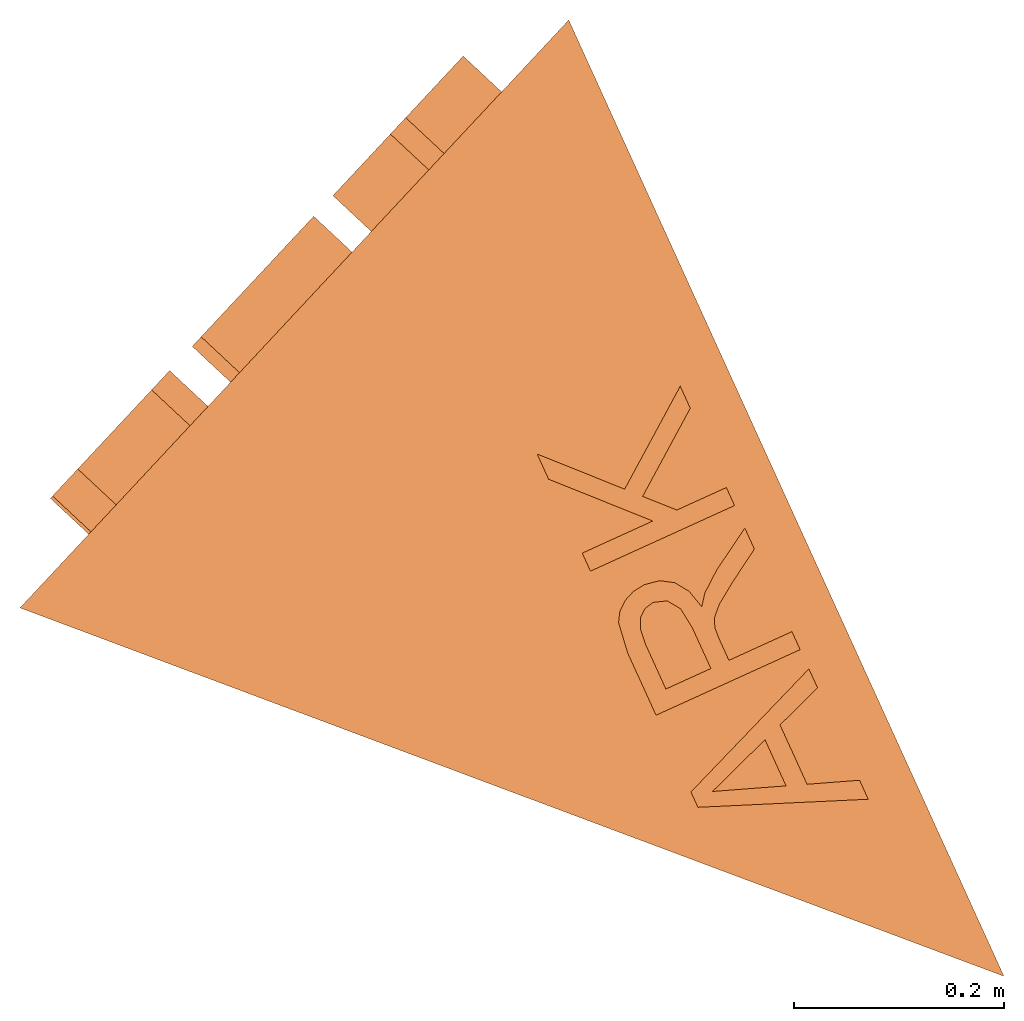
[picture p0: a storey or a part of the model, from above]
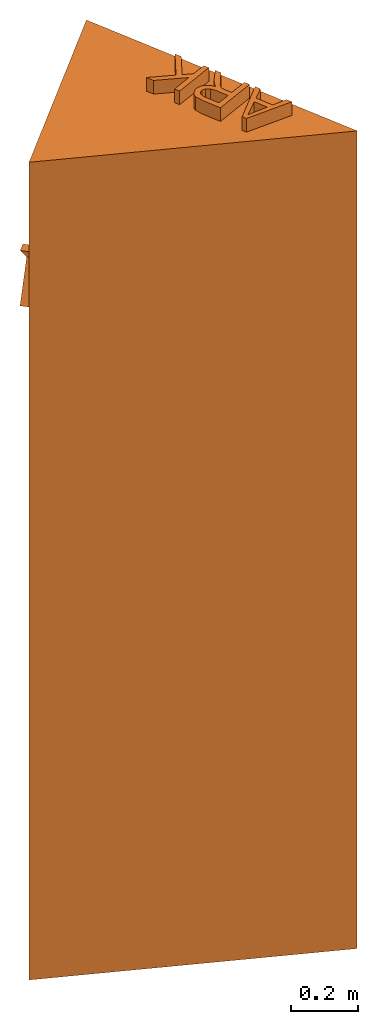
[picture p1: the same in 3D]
Properties of the parts of a building model (IFC4)

# File
Description: ViewDefinition [ReferenceView_V1.2], RevitIdentifiers [ContentGUID: 9cd8e079-0436-4ea4-8650-3dddd296d1fd, VersionGUID: 580e8274-afbe-421e-a8b7-224c4fa81504, NumberOfSaves: 417], CoordinateReference [CoordinateBase: Shared Coordinates, ProjectSite: Internal]
File name: A_52508566_Brannstasjon Drevsjø2.ifc
Time: 2026-09-22T08:41:08+01:00
Written by: ODA SDAI 25.12
Made in: Autodesk - Revit 26.4.0.32 (ENU) - 26.4.10.8

# IfcProject, 52508566
LongName: Brannstasjon Drevsjø; Phase: -

# IfcSite, Tomtens navn
RefLatitude: 59, 54, 57, 601318; RefLongitude: 10, 44, 59, 999999; RefElevation: 0 mm

# IfcBuilding, Byggets navn
LongName: Byggets navn

# IfcBuildingStorey (5)
In: Byggets navn
Name | LongName | Elevation (mm)
Level U1 | Level U1 | -3000
0-Sea Level | 0-Sea Level | 0
Level 01 | Level 01 | 2.19937e-25
Level 02 | Level 02 | 3500
Level 3 | Level 3 | 7000

# IfcSpace: BK 121:2084863, 121
In: Level 01
LongName: BK

# IfcSpace: Data 203:1993968, 203
In: Level 02
LongName: Data

# IfcSpace: Dusj D 109:1964507, 109
In: Level 01
LongName: Dusj D

# IfcSpace: Dusj H 107:1964497, 107
In: Level 01
LongName: Dusj H

# IfcSpace: EL. 122:2086236, 122
In: Level 01
LongName: EL.

# IfcSpace: Fingard. damer 104:1964506, 104
In: Level 01
LongName: Fingard. damer

# IfcSpace: Fingard. herrer 103:1964496, 103
In: Level 01
LongName: Fingard. herrer

# IfcSpace: Garasje skogbrannberedskap 118:1971460, 118
In: Level 01
LongName: Garasje skogbrannberedskap

# IfcSpace: Grovgard. d 110:1964504, 110
In: Level 01
LongName: Grovgard. d

# IfcSpace: Grovgard. h 108:1964503, 108
In: Level 01
LongName: Grovgard. h

# IfcSpace: Grovvask/lomp 111:1964502, 111
In: Level 01
LongName: Grovvask/lomp

# IfcSpace: Korridor 101:1964493, 101
In: Level 01
LongName: Korridor

# IfcSpace: Mesanin 204:1981262, 204
In: Level 02
LongName: Mesanin

# IfcSpace: Platting 206:2002072, 206
In: Level 02
LongName: Platting

# IfcSpace: Rapport 205:2087642, 205
In: Level 02
LongName: Rapport

# IfcSpace: Sivilforsvaret 131:2087587, 131
In: Level 01
LongName: Sivilforsvaret

# IfcSpace: Teknisk 120:2077556, 120
In: Level 01
LongName: Teknisk

# IfcSpace: Teknisk 202:1964515, 202
In: Level 02
LongName: Teknisk

# IfcSpace: Ubrukt areal 201:2080696, 201
In: Level 02
LongName: Ubrukt areal

# IfcSpace: Utrykningsgarderobe 102:1964509, 102
In: Level 01
LongName: Utrykningsgarderobe

# IfcSpace: Utstyrsrom/lager 115:1964525, 115
In: Level 01
LongName: Utstyrsrom/lager

# IfcSpace: VF 124:2093019, 124
In: Level 01
LongName: VF

# IfcSpace: Vask-tørk 113:1964501, 113
In: Level 01
LongName: Vask-tørk

# IfcSpace: Vaskehall 119:2018025, 119
In: Level 01
LongName: Vaskehall

# IfcSpace: Vognhall spor 1 117:1964524, 117
In: Level 01
LongName: Vognhall spor 1

# IfcSpace: Vognhall spor 2 116:1964523, 116
In: Level 01
LongName: Vognhall spor 2

# IfcSpace: WC 105:1964498, 105
In: Level 01
LongName: WC

# IfcSpace: WC 106:1964508, 106
In: Level 01
LongName: WC

# IfcSpace: WC 112:1964505, 112
In: Level 01
LongName: WC

# IfcSpace: WC 123:2093000, 123
In: Level 01
LongName: WC

# IfcBuildingElementPart (363)
Name | In | Material
12 x Metall - Malt overflate - Mørk Grå, Matt | Level 01 | Metall - Malt overflate - Mørk Grå, Matt
16 x Rustfritt Stål | Level 01 | Rustfritt Stål
19 x NO_Isolasjon - Fast | Level 01 | NO_Isolasjon - Fast
53 x Gipsplater | Level 01 | Gipsplater
41 x Stender | Level 01 | Stender
Floor:Gulv på grunn 120mm:1964344 | Level 01
4 x NO_Betong - Plasstøpt | Level 01 | NO_Betong - Plasstøpt
20 x NO_platekledning forestia | Level 01 | NO_platekledning forestia
24 x NO_Kryssfiner | Level 01 | NO_Kryssfiner
18 x NO_Baderomsplater | Level 01 | NO_Baderomsplater
2 x NO_Maling - rød | Level 02 | NO_Maling - rød
12 x Rustfritt Stål | Level 02 | Rustfritt Stål
10 x NO_Isolasjon - Fast | Level 02 | NO_Isolasjon - Fast
6 x Metall - Malt overflate - Mørk Grå, Matt | Level 02 | Metall - Malt overflate - Mørk Grå, Matt
5 x NO_Betong - Plasstøpt | Level 02 | NO_Betong - Plasstøpt
2 x NO_Vinyl | Level 02 | NO_Vinyl
2 x Floor:HD-320+ isolasjon og avretting:1964411 | Level 02
5 x Metall - Malt overflate - Mørk Grå, Matt | Level 3 | Metall - Malt overflate - Mørk Grå, Matt
6 x Rustfritt Stål | Level 3 | Rustfritt Stål
6 x NO_Isolasjon - Fast | Level 3 | NO_Isolasjon - Fast
NO_Himling (type ikke bestemt) | 104 | NO_Himling (type ikke bestemt)
NO_Himling 600x600 | 104 | NO_Himling 600x600
NO_Himling (type ikke bestemt) | 110 | NO_Himling (type ikke bestemt)
NO_Himling 600x600 | 110 | NO_Himling 600x600
NO_Himling (type ikke bestemt) | 109 | NO_Himling (type ikke bestemt)
NO_Himling 600x600 hygiene | 109 | NO_Himling 600x600 hygiene
NO_Himling (type ikke bestemt) | 103 | NO_Himling (type ikke bestemt)
NO_Himling 600x600 | 103 | NO_Himling 600x600
NO_Himling (type ikke bestemt) | 107 | NO_Himling (type ikke bestemt)
NO_Himling 600x600 hygiene | 107 | NO_Himling 600x600 hygiene
NO_Himling (type ikke bestemt) | 108 | NO_Himling (type ikke bestemt)
NO_Himling 600x600 | 108 | NO_Himling 600x600
NO_Himling (type ikke bestemt) | Level 01 | NO_Himling (type ikke bestemt)
NO_Himling 600x600 | Level 01 | NO_Himling 600x600
NO_Himling (type ikke bestemt) | 111 | NO_Himling (type ikke bestemt)
NO_Himling 600x600 | 111 | NO_Himling 600x600
4 x NO_platekledning | Level 01 | NO_platekledning
NO_Gips | Level 02 | NO_Gips
NO_Konstruksjon - Isolert | Level 02 | NO_Konstruksjon - Isolert
3 x NO_Konstruksjon - Isolert | Level 01 | NO_Konstruksjon - Isolert
NO_Himling (type ikke bestemt) | 101 | NO_Himling (type ikke bestemt)
NO_Himling 600x600 | 101 | NO_Himling 600x600
6 x NO_Maling - mørk grå | Level 01 | NO_Maling - mørk grå
6 x 231_Vegg 250mm_Betong | Level 01 | 231_Vegg 250mm_Betong
19 x Gipsplater | Level 02 | Gipsplater
2 x NO_platekledning forestia | Level 02 | NO_platekledning forestia
9 x Stender | Level 02 | Stender
NO_Metall - Rustfritt Stål-rist | Level 01 | NO_Metall - Rustfritt Stål-rist
NO_Himling (type ikke bestemt) | 106 | NO_Himling (type ikke bestemt)
NO_Himling 600x600 | 106 | NO_Himling 600x600
3 x NO_platekledning | Level 02 | NO_platekledning
NO_Himling (type ikke bestemt) | 112 | NO_Himling (type ikke bestemt)
NO_Himling 600x600 | 112 | NO_Himling 600x600
NO_Himling (type ikke bestemt) | 105 | NO_Himling (type ikke bestemt)
NO_Himling 600x600 | 105 | NO_Himling 600x600
NO_Himling (type ikke bestemt) | 113 | NO_Himling (type ikke bestemt)
NO_Himling 600x600 | 113 | NO_Himling 600x600
Floor:HD-320 mesanin +30mm:1981251 | Level 02
5 x NO_Kryssfiner | Level 02 | NO_Kryssfiner
NO_Himling (type ikke bestemt) | 120 | NO_Himling (type ikke bestemt)
NO_Himling 600x600 | 120 | NO_Himling 600x600
NO_Maling - rød | Level 01 | NO_Maling - rød
NO_Maling - rød | Level 3 | NO_Maling - rød
NO_Himling (type ikke bestemt) | 205 | NO_Himling (type ikke bestemt)
NO_Himling 600x600 | 205 | NO_Himling 600x600
NO_Himling (type ikke bestemt) | 121 | NO_Himling (type ikke bestemt)
NO_Himling 600x600 | 121 | NO_Himling 600x600
NO_Himling (type ikke bestemt) | 123 | NO_Himling (type ikke bestemt)
NO_Himling 600x600 | 123 | NO_Himling 600x600
NO_Himling (type ikke bestemt) | 124 | NO_Himling (type ikke bestemt)
NO_Himling 600x600 | 124 | NO_Himling 600x600

# IfcBuildingElementProxy: Computer_Desktop_X-ray_PACs_screens_and_keyboard_13483:Computer_Desktop_X-ray_PACs_screens_and_keyboard_13483 (2)
In: 205
Type - Material: -Computer Monitor PACs Decal, -Computer Monitor Plastic Black, <Unnamed>, - Computer Plastic Black, -Computer Keyboard Decal, Alumium, Plastic White
Name (Computer_Desktop_X-ray_PACs_screens_and_keyboard_13483:Computer_Desktop_X-ray_PACs_screens_and_keyboard_13483:...)
2106597
2106598

# IfcBuildingElementProxy: Dishwasher:Dishwasher, Dishwasher:Dishwasher:2097757
In: 205
Type - Material: <Unnamed>

# IfcBuildingElementProxy: Dryer:750x1200x1850 mm, Dryer:750x1200x1850 mm:1964970
In: 113
Type - Material: <Unnamed>, Black

# IfcBuildingElementProxy: Dryer:Tørkeskap 600x6000x1850 mm (2)
In: 113
Type - Material: <Unnamed>, Black
Name (Dryer:Tørkeskap 600x6000x1850 mm:...)
1965009
1965107

# IfcBuildingElementProxy: Handtag skåp1:Handtag skåp (34)
Type - Material: Handtag, vitt
Name (Handtag skåp1:Handtag skåp:...) | In
1965055 | 102
1965056 | 102
1965058 | 102
1965059 | 102
1965061 | 102
1965062 | 102
1965064 | 102
1965065 | 102
1965067 | 102
1965068 | 102
1965070 | 102
1965071 | 102
1965073 | 102
1965074 | 102
1965076 | 102
1965077 | 102
1965079 | 102
1965080 | 102
1965082 | 102
1965083 | 102
1965085 | 102
1965086 | 102
1965088 | 102
1965089 | 102
1965091 | 102
1965092 | 102
1965094 | 102
1965095 | 102
1965097 | 102
1965098 | 102
1965100 | 102
1965101 | 102
2084983 | 121
2084984 | 121

# IfcBuildingElementProxy: Microwave:600 x 400 x 400mm, Microwave:600 x 400 x 400mm:2098127
In: 205
Type - Material: <Unnamed>

# IfcBuildingElementProxy: NO_Origo:ARK, NO_Origo:ARK:921652
In: Level U1
Type - Material: ARK, <Unnamed>

# IfcBuildingElementProxy: Pantry_Shelving:W900 D545 (2)
In: 119
Type - Material: <Unnamed>, Shelf Top
Name (Pantry_Shelving:W900 D545:...)
2105331
2105332

# IfcBuildingElementProxy: Printer-Copier:Printer, Printer-Copier:Printer:2106596
In: 205
Type - Material: Plastic - ABS, White, Plastic - ABS, Grey, Plastic - Polycarbonate, Black
Classification: E1010800 Office Equipment (Uniformat)

# IfcBuildingElementProxy: Refrigerator_Under Counter:600x600x860mm, Refrigerator_Under Counter:600x600x860mm:2102702
In: 205
Type - Material: <Unnamed>

# IfcBuildingElementProxy: Special Equipment_Ladder_Cage:Standard, Special Equipment_Ladder_Cage:Standard:2122300
In: Level 01
Type - Material: <Unnamed>

# IfcBuildingElementProxy: Washer:1200x900x1800 mm klær, Washer:1200x900x1800 mm klær:1964969
In: 111
Type - Material: <Unnamed>

# IfcBuildingElementProxy: Washer:1290x850x1800 mm utstyr, Washer:1290x850x1800 mm utstyr:1964957
In: 111
Type - Material: <Unnamed>

# IfcBuildingElementProxy: Washer:600x600x850 mm, Washer:600x600x850 mm:1964958
In: 113
Type - Material: <Unnamed>

# IfcCovering: Compound Ceiling:H01 257_Systemhimling 600x600, tykkelse 100 (16)
Type - PredefinedType: CEILING
Name (Compound Ceiling:H01 257_Systemhimling 600x600, tykkelse 100:...) | In
1964538 | 104
1964545 | 110
1964664 | 103
1964678 | 108
1964685 | Level 01
1964692 | 111
1964847 | 101
1965118 | 106
1965170 | 112
1965181 | 105
1965213 | 113
2031679 | 120
2099162 | 205
2117964 | 121
2118016 | 123
2118024 | 124

# IfcCovering: Compound Ceiling:H02 257_Systemhimling 600x600, hygiene (2)
Type - PredefinedType: CEILING
Name (Compound Ceiling:H02 257_Systemhimling 600x600, hygiene:...) | In
1964552 | 109
1964671 | 107

# IfcDistributionPort (10)
Description: Flow; FlowDirection: SINK; PredefinedType: PIPE
Name | SystemType
InPort_1964533_1 | DOMESTICHOTWATER
InPort_1964533_2 | DOMESTICCOLDWATER
InPort_1964971_1 | DOMESTICHOTWATER
InPort_1964971_2 | DOMESTICCOLDWATER
InPort_1992489_1 | DOMESTICHOTWATER
InPort_1992489_2 | DOMESTICCOLDWATER
InPort_2084714_1 | DOMESTICHOTWATER
InPort_2084714_2 | DOMESTICCOLDWATER
InPort_2116596_1 | DOMESTICHOTWATER
InPort_2116596_2 | DOMESTICCOLDWATER

# IfcDoor: ASSA_ABLOY_FoldingDoor_FD2350P_2+2_Manual:42x45 (2)
In: Level 01
Type - PredefinedType: DOOR; Material: <Unnamed>, Aluminum - Assa Abloy - Black, Steel - Assa Abloy - Paint Finish RAL 3002 - Red
OverallHeight: 4500 mm; OverallWidth: 4200 mm; Classification: B2030 Exterior Doors (Uniformat)
Name (ASSA_ABLOY_FoldingDoor_FD2350P_2+2_Manual:42x45:...)
1967829
1967928

# IfcDoor: Enfløyet:ID02 11x21M, Enfløyet:ID02 11x21M:1992485
In: Level 02
Type - PredefinedType: DOOR; OperationType: SINGLE_SWING_LEFT; Material: Rustfritt Stål, Hvit (2)
Type - Enfløyet:ID02 11x21M:1992485:1 - PanelOperation: SWINGING
OverallHeight: 2110 mm; OverallWidth: 1110 mm; Material: Rustfritt Stål, Hvit

# IfcDoor: Enfløyet:ID03 Tredør 11x21M - EI30 (2)
In: Level 02
Type - PredefinedType: DOOR; OperationType: SINGLE_SWING_LEFT; Material: Rustfritt Stål, Hvit (2)
Type - Enfløyet:ID03 Tredør 11x21M - EI30:1992797:1 - PanelOperation: SWINGING
OverallHeight: 2110 mm; OverallWidth: 1110 mm; Material: Rustfritt Stål, Hvit
Name (Enfløyet:ID03 Tredør 11x21M - EI30:...)
1992797
2086316

# IfcDoor: Enfløyet:ID04 Tredør 9x21M, Enfløyet:ID04 Tredør 9x21M:2092488
In: Level 01
Type - PredefinedType: DOOR; OperationType: SINGLE_SWING_LEFT; Material: Rustfritt Stål, NO_Maling - Hvit, Hvit
Type - Enfløyet:ID04 Tredør 9x21M:2092488:1 - PanelOperation: SWINGING
OverallHeight: 2110 mm; OverallWidth: 910 mm

# IfcDoor: Enfløyet:ID04 Tredør 9x21M, Enfløyet:ID04 Tredør 9x21M:1964951
In: Level 01
Type - PredefinedType: DOOR; OperationType: SINGLE_SWING_RIGHT; Material: Rustfritt Stål, NO_Maling - Hvit, Hvit
Type - Enfløyet:ID04 Tredør 9x21M:1964951:1 - PanelOperation: SWINGING
OverallHeight: 2110 mm; OverallWidth: 910 mm

# IfcDoor: Enfløyet:ID04 Tredør 9x21M (2)
In: Level 01
Type - PredefinedType: DOOR; OperationType: SINGLE_SWING_RIGHT; Material: Rustfritt Stål, NO_Maling - Hvit, Hvit
Type - Enfløyet:ID04 Tredør 9x21M:1964952:1 - PanelOperation: SWINGING
OverallHeight: 2110 mm; OverallWidth: 910 mm
Name (Enfløyet:ID04 Tredør 9x21M:...)
1964952
1964973

# IfcDoor: Enfløyet:ID05 Komposittdør 10x21M (2)
In: Level 01
Type - PredefinedType: DOOR; OperationType: SINGLE_SWING_RIGHT; Material: Rustfritt Stål, Hvit (2)
Type - Enfløyet:ID05 Komposittdør 10x21M:1964434:1 - PanelOperation: SWINGING
OverallHeight: 2110 mm; OverallWidth: 1010 mm; Material: Rustfritt Stål, Hvit
Name (Enfløyet:ID05 Komposittdør 10x21M:...)
1964434
1964435

# IfcDoor: Enfløyet:ID06 Tredør 10x21M, Enfløyet:ID06 Tredør 10x21M:1964431
In: Level 01
Type - PredefinedType: DOOR; OperationType: SINGLE_SWING_LEFT; Material: Rustfritt Stål, Hvit (2)
Type - Enfløyet:ID06 Tredør 10x21M:1964431:1 - PanelOperation: SWINGING
OverallHeight: 2110 mm; OverallWidth: 1010 mm; Material: Rustfritt Stål, Hvit

# IfcDoor: Enfløyet:ID06 Tredør 10x21M (2)
In: Level 01
Type - PredefinedType: DOOR; OperationType: SINGLE_SWING_LEFT; Material: Rustfritt Stål, Hvit (2)
Type - Enfløyet:ID06 Tredør 10x21M:1964948:1 - PanelOperation: SWINGING
OverallHeight: 2110 mm; OverallWidth: 1010 mm; Material: Rustfritt Stål, Hvit
Name (Enfløyet:ID06 Tredør 10x21M:...)
1964948
1964949

# IfcDoor: Enfløyet:ID07 Tredør 10x21M EI60, Enfløyet:ID07 Tredør 10x21M EI60:1964855
In: Level 01
Type - PredefinedType: DOOR; OperationType: SINGLE_SWING_RIGHT; Material: Rustfritt Stål, Hvit (2)
Type - Enfløyet:ID07 Tredør 10x21M EI60:1964855:1 - PanelOperation: SWINGING
OverallHeight: 2110 mm; OverallWidth: 1010 mm; Material: Rustfritt Stål, Hvit

# IfcDoor: Enfløyet:ID08 11x21M EI60CSa, Enfløyet:ID08 11x21M EI60CSa:1964432
In: Level 01
Type - PredefinedType: DOOR; OperationType: SINGLE_SWING_LEFT; Material: Rustfritt Stål, Hvit (2)
Type - Enfløyet:ID08 11x21M EI60CSa:1964432:1 - PanelOperation: SWINGING
OverallHeight: 2110 mm; OverallWidth: 1110 mm; Material: Rustfritt Stål, Hvit

# IfcDoor: Enfløyet:ID09 ståldør 13x21M EI30 2, Enfløyet:ID09 ståldør 13x21M EI30 2:1964436
In: Level 01
Type - PredefinedType: DOOR; OperationType: SINGLE_SWING_RIGHT; Material: Rustfritt Stål, Hvit (2)
Type - Enfløyet:ID09 ståldør 13x21M EI30 2:1964436:1 - PanelOperation: SWINGING
OverallHeight: 2110 mm; OverallWidth: 1310 mm; Material: Rustfritt Stål, Hvit

# IfcDoor: Enfløyet:ID1 Glassdør 11x21M 38dB, Enfløyet:ID1 Glassdør 11x21M 38dB:2087617
In: Level 02
Type - PredefinedType: DOOR; OperationType: SINGLE_SWING_LEFT; Material: Rustfritt Stål, Hvit (2), NO_Glass
Type - Enfløyet:ID1 Glassdør 11x21M 38dB:2087617:1 - PanelOperation: SWINGING
OverallHeight: 2110 mm; OverallWidth: 1110 mm; Material: Rustfritt Stål, Hvit, NO_Glass

# IfcDoor: Enfløyet:ID10 Stålsdør 10x21M, Enfløyet:ID10 Stålsdør 10x21M:2092397
In: Level 01
Type - PredefinedType: DOOR; OperationType: SINGLE_SWING_LEFT; Material: Rustfritt Stål, Hvit (2)
Type - Enfløyet:ID10 Stålsdør 10x21M:2092397:1 - PanelOperation: SWINGING
OverallHeight: 2110 mm; OverallWidth: 1010 mm; Material: Rustfritt Stål, Hvit

# IfcDoor: Enfløyet:ID11 Tredør 10x21M (2)
In: Level 01
Type - PredefinedType: DOOR; OperationType: SINGLE_SWING_LEFT; Material: Rustfritt Stål, Hvit (2)
Type - Enfløyet:ID11 Tredør 10x21M:1964950:1 - PanelOperation: SWINGING
OverallHeight: 2110 mm; OverallWidth: 1010 mm; Material: Rustfritt Stål, Hvit
Name (Enfløyet:ID11 Tredør 10x21M:...)
1964950
2085154

# IfcDoor: Enfløyet:ID11 Tredør 10x21M, Enfløyet:ID11 Tredør 10x21M:1964953
In: Level 01
Type - PredefinedType: DOOR; OperationType: SINGLE_SWING_RIGHT; Material: Rustfritt Stål, Hvit (2)
Type - Enfløyet:ID11 Tredør 10x21M:1964953:1 - PanelOperation: SWINGING
OverallHeight: 2110 mm; OverallWidth: 1010 mm; Material: Rustfritt Stål, Hvit

# IfcDoor: Enfløyet:ID13 Ståldør 10x21M EI30Sa, Enfløyet:ID13 Ståldør 10x21M EI30Sa:2077570
In: Level 01
Type - PredefinedType: DOOR; OperationType: SINGLE_SWING_LEFT; Material: Rustfritt Stål, Hvit (2)
Type - Enfløyet:ID13 Ståldør 10x21M EI30Sa:2077570:1 - PanelOperation: SWINGING
OverallHeight: 2110 mm; OverallWidth: 1010 mm; Material: Rustfritt Stål, Hvit

# IfcDoor: Enfløyet:YD01 Glassdør sprosse 11x21M, Enfløyet:YD01 Glassdør sprosse 11x21M:2075855
In: Level 01
Type - PredefinedType: DOOR; OperationType: SINGLE_SWING_LEFT; Material: Rustfritt Stål, NO_Maling - mørk grå, NO_Glass - Klart, NO_Maling - sort
Type - Enfløyet:YD01 Glassdør sprosse 11x21M:2075855:1 - PanelOperation: SWINGING
OverallHeight: 2110 mm; OverallWidth: 1110 mm

# IfcDoor: Enfløyet:YD02 Ytterdør 11x21M mørk grå, Enfløyet:YD02 Ytterdør 11x21M mørk grå:2087068
In: Level 01
Type - PredefinedType: DOOR; OperationType: SINGLE_SWING_LEFT; Material: Rustfritt Stål, NO_Maling - mørk grå, NO_Maling - sort
Type - Enfløyet:YD02 Ytterdør 11x21M mørk grå:2087068:1 - PanelOperation: SWINGING
OverallHeight: 2110 mm; OverallWidth: 1110 mm

# IfcDoor: Enfløyet:YD02 Ytterdør 11x21M mørk grå, Enfløyet:YD02 Ytterdør 11x21M mørk grå:1970705
In: Level 01
Type - PredefinedType: DOOR; OperationType: SINGLE_SWING_RIGHT; Material: Rustfritt Stål, NO_Maling - mørk grå, NO_Maling - sort
Type - Enfløyet:YD02 Ytterdør 11x21M mørk grå:1970705:1 - PanelOperation: SWINGING
OverallHeight: 2110 mm; OverallWidth: 1110 mm

# IfcDoor: Garage Door_3:P03 2500 x 2100, Garage Door_3:P03 2500 x 2100:1964530
In: Level 01
Type - PredefinedType: DOOR; Material: NO_Door - Frame Painted, Beslag, <Unnamed>, NO_Door - Panel
OverallHeight: 2100 mm; OverallWidth: 2500 mm

# IfcDoor: Garage Door_9:4200 x 4500, Garage Door_9:4200 x 4500:1965248
In: Level 01
Type - PredefinedType: DOOR; Material: Steel - Assa Abloy - Paint Finish RAL 3002 - Red (2), NO_Glass - Klart, NO_Door - Frame Painted
OverallHeight: 4500 mm; OverallWidth: 4200 mm; Material: Steel - Assa Abloy - Paint Finish RAL 3002 - Red, NO_Glass - Klart, NO_Door - Frame Painted

# IfcDoor: Garage Door_9:4200 x 4500 P02B, Garage Door_9:4200 x 4500 P02B:2087061
In: Level 01
Type - PredefinedType: DOOR; Material: Steel - Assa Abloy - Paint Finish RAL 3002 - Red (2), NO_Glass - Klart, NO_Door - Frame Painted
OverallHeight: 4500 mm; OverallWidth: 4200 mm; Material: Steel - Assa Abloy - Paint Finish RAL 3002 - Red, NO_Glass - Klart, NO_Door - Frame Painted

# IfcDoor: Garage Door_9:P04 2700 x 3000, Garage Door_9:P04 2700 x 3000:1971641
In: Level 01
Type - PredefinedType: DOOR; Material: Steel - Assa Abloy - Paint Finish RAL 3002 - Red (2), NO_Glass - Klart, NO_Door - Frame Painted
OverallHeight: 3000 mm; OverallWidth: 2700 mm; Material: Steel - Assa Abloy - Paint Finish RAL 3002 - Red, NO_Glass - Klart, NO_Door - Frame Painted

# IfcDoor: M_Door_ID_Cased-Opening:1200 x 2110mm 2, M_Door_ID_Cased-Opening:1200 x 2110mm 2:1964433
In: Level 01
Type - PredefinedType: DOOR; Material: <Unnamed>
OverallHeight: 2110 mm; OverallWidth: 1200 mm

# IfcDoor: M_Door_ID_Cased-Opening:910 x 2110mm (2)
In: Level 01
Type - PredefinedType: DOOR; Material: <Unnamed>
OverallHeight: 2110 mm; OverallWidth: 910 mm
Name (M_Door_ID_Cased-Opening:910 x 2110mm:...)
1965007
1965008

# IfcDoor: Tofløyet:ID12 Stålsdør 16x21M EI30Sa, Tofløyet:ID12 Stålsdør 16x21M EI30Sa:2076329
In: Level 01
Type - PredefinedType: DOOR; OperationType: DOUBLE_DOOR_SINGLE_SWING; Material: Hvit (2), Rustfritt Stål
Type - Tofløyet:ID12 Stålsdør 16x21M EI30Sa:2076329:1 - PanelDepth: 40 mm; PanelOperation: SWINGING; PanelWidth: 0.374214; PanelPosition: LEFT
Type - Tofløyet:ID12 Stålsdør 16x21M EI30Sa:2076329:2 - PanelDepth: 40 mm; PanelOperation: SWINGING; PanelWidth: 0.625786; PanelPosition: RIGHT
OverallHeight: 2110 mm; OverallWidth: 1610 mm; Material: Hvit, Rustfritt Stål

# IfcDoor: Tofløyet:ID14 Tredør 16x21M EI30Sa, Tofløyet:ID14 Tredør 16x21M EI30Sa:2085995
In: Level 01
Type - PredefinedType: DOOR; OperationType: DOUBLE_DOOR_SINGLE_SWING; Material: Hvit (2), Rustfritt Stål
Type - Tofløyet:ID14 Tredør 16x21M EI30Sa:2085995:1 - PanelDepth: 40 mm; PanelOperation: SWINGING; PanelWidth: 0.374214; PanelPosition: LEFT
Type - Tofløyet:ID14 Tredør 16x21M EI30Sa:2085995:2 - PanelDepth: 40 mm; PanelOperation: SWINGING; PanelWidth: 0.625786; PanelPosition: RIGHT
OverallHeight: 2110 mm; OverallWidth: 1610 mm; Material: Hvit, Rustfritt Stål

# IfcFlowTerminal: IS_Ceraflex_B5128_BIM_IT:B5128AA - CERAFLEX SNK MXR EXPSD TUB.SPT/235MM (5)
Type - Material: 2af18724_cdc2_442c_8398_5f3f990449a0
Classification: C1030200 Bath & Toilet Accessories (Uniformat)
Name (IS_Ceraflex_B5128_BIM_IT:B5128AA - CERAFLEX SNK MXR EXPSD TUB.SPT/235MM:...) | In
1964533 | 116
1964971 | 113
1992489 | 202
2084714 | 121
2116596 | 131

# IfcFlowTerminal: M_Sink Kitchen-Single:760 x 535mm, M_Sink Kitchen-Single:760 x 535mm:2098303
In: 205
Type - Material: Metal - Steel, Polished

# IfcFlowTerminal: Shower_01:Shower_01 (5)
Type - Material: <Unnamed>
Name (Shower_01:Shower_01:...) | In
1964766 | 109
1964767 | 109
1964961 | 107
1964986 | 107
1964987 | 107

# IfcFlowTerminal: Sink Vanity-Square:700 x500 x 300 (2)
In: 111
Type - Material: EU_Metal Aluminium, Polished Plain, EU_Metal Stainless Steel, Polished Plain
Name (Sink Vanity-Square:700 x500 x 300:...)
1965011
1965012

# IfcFlowTerminal: Sink Vanity-Square:900 x 700 x 500, Sink Vanity-Square:900 x 700 x 500:1965010
In: 111
Type - Material: EU_Metal Aluminium, Polished Plain, EU_Metal Stainless Steel, Polished Plain

# IfcFlowTerminal: Sink_01:500x350 (8)
Type - Material: Metal - Chrome, Porslin
Name (Sink_01:500x350:...) | In
1964946 | 108
1964947 | 110
1964963 | 105
1964964 | 104
1964967 | 112
1964968 | 103
1964984 | 106
2092192 | 123

# IfcFlowTerminal: Sink_03:Middels (5)
Type - Material: Metal - Aluminium
Name (Sink_03:Middels:...) | In
1964534 | 116
1965023 | 113
1993845 | 202
2084552 | 121
2116409 | 131

# IfcFlowTerminal: WC-Wall:Wall_Hung_WC-Valverfa_2893[1] (4)
Type - Material: Seat Finish, Pan Finish
Name (WC-Wall:Wall_Hung_WC-Valverfa_2893[1]:...) | In
1964945 | 105
1964976 | 112
1964982 | 106
2091680 | 123

# IfcFurniture: Benkeskap-3 skuff:600, Benkeskap-3 skuff:600:2098304
In: 205
Type - Material: Cabinets, <Unnamed>

# IfcFurniture: Chair Desk 2:Chair-Task Arms (2)
In: 205
Type - Material: Textile - Slate Blue, Plastic - Black
Classification: E2020200 Furniture & Accessories (Uniformat)
Name (Chair Desk 2:Chair-Task Arms:...)
2106594
2106595

# IfcFurniture: Detention_Bunk-WallMnt:Double-Bunk, Detention_Bunk-WallMnt:Double-Bunk:2106600
In: 205
Type - Material: <Unnamed>
Classification: E1020600 Detention Equipment (Uniformat)

# IfcFurniture: Overskap-Enkel dør:600 (2)
In: 205
Type - Material: Cabinets
Name (Overskap-Enkel dør:600:...)
2098632
2099032

# IfcFurniture: Overskap-Enkel dør:600 H500, Overskap-Enkel dør:600 H500:2098573
In: 205
Type - Material: Cabinets

# IfcFurniture: PLANK_BENCH_TABLE:0660-01 NATURAL (6)
In: 102
Type - Material: PLANK_WOOD_NATURAL
Name (PLANK_BENCH_TABLE:0660-01 NATURAL:...)
1965013
1965015
1965016
1965017
1965102
1965103

# IfcFurniture: PLANK_BENCH_TABLE:Benk 1200, PLANK_BENCH_TABLE:Benk 1200:1965111
In: 103
Type - Material: PLANK_WOOD_NATURAL

# IfcFurniture: Storage_Shelf_01:Oppbevaring B800xD600xH1800 2 (7)
In: 115
Type - Material: <Unnamed>
Classification: E2020200 Furniture & Accessories (Uniformat)
Name (Storage_Shelf_01:Oppbevaring B800xD600xH1800 2:...)
1965188
1965189
1965190
1965191
1965192
1965193
1965194

# IfcFurniture: Table_01:H500 D700 W1200 (2)
Type - Material: <Unnamed>
Name (Table_01:H500 D700 W1200:...) | In
1964978 | 111
1964979 | 113

# IfcFurniture: Table_Office_01:72" 1200 lang, Table_Office_01:72" 1200 lang:2106599
In: 205
Type - Material: Furniture_Watson_Seven_Leg, <Unnamed>

# IfcFurniture: Table_Office_01:72" 3100 mm lang, Table_Office_01:72" 3100 mm lang:2106593
In: 205
Type - Material: Furniture_Watson_Seven_Leg, <Unnamed>

# IfcFurniture: Wardrobe Double:700 (16)
In: 102
Type - Material: Skåpstomme, vit (2), Skåpdörr, vit
Material: Skåpstomme, vit, Skåpdörr, vit
Name (Wardrobe Double:700:...)
1965054
1965057
1965060
1965063
1965066
1965069
1965072
1965075
1965078
1965081
1965084
1965087
1965090
1965093
1965096
1965099

# IfcFurniture: Wardrobe Double:800 2, Wardrobe Double:800 2:2084982
In: 121
Type - Material: Skåpstomme, vit (2), Skåpdörr, vit
Material: Skåpstomme, vit, Skåpdörr, vit

# IfcFurniture: Worktop:600mm Depth uten vask eller utfresning, Worktop:600mm Depth uten vask eller utfresning:1970112
In: 116
Type - Material: Counter Top

# IfcFurniture: Worktop:800mm Depth uten vask, Worktop:800mm Depth uten vask:1964965
In: 111
Type - Material: Counter Top

# IfcFurniture: Worktop:with sink, Worktop:with sink:2098301
In: 205
Type - Material: Counter Top

# IfcFurniture: ^ 275_Public_Locker02 x2 w Bench:300x300+200 (10)
Type - Material: Paint - Grey, Paint - White
Name (^ 275_Public_Locker02 x2 w Bench:300x300+200:...) | In
1964750 | 104
1964751 | 104
1964752 | 104
1964753 | 104
1964755 | 103
1964756 | 103
1964757 | 103
1964758 | 103
1964759 | 103
1965112 | 103

# IfcMember: Stringer:Stringer - Metal - 45 mm Width (10)
In: Level 01
Type - PredefinedType: STRINGER
Material: Stål
Name (Assembled Stair:Stair:...)
1964990 Stringer 1
1964990 Stringer 2
2088389 Stringer 1
2088389 Stringer 2
2088389 Stringer 3
2088389 Stringer 4
2088389 Stringer 5
2088389 Stringer 6
2088389 Stringer 7
2088389 Stringer 8

# IfcOpeningElement (73)
PredefinedType: OPENING
Name | In
2 x Basic Wall:IV20 242- Utforing isolert Stender(95) gips:1964762:1 | Level 02
2 x Basic Wall:IV20 242- Utforing isolert Stender(95) gips:1964762:2 | Level 02
2 x Basic Wall:IV20 242- Utforing isolert Stender(95) gips:1964762:3 | Level 02
Basic Wall:IV15 Gips kryssfiner 95 stålstender +15mm kryssfiner+baderomsplater 2:1964960:1 | Level 01
Basic Wall:IV11 95 Utforing 15mm kryssfiner baderomsplater 2:1965105:1 | Level 01
3 x Basic Wall:YV02 Sandwichvegg 200:2095643:1 | Level 02
3 x Basic Wall:YV02 Sandwichvegg 200:2095643:2 | Level 02
3 x Basic Wall:YV02 Sandwichvegg 200:2095643:3 | Level 02
3 x Basic Wall:YV02 Sandwichvegg 200:2095643:4 | Level 02
3 x Basic Wall:YV02 Sandwichvegg 200:2095643:5 | Level 02
3 x Basic Wall:YV02 Sandwichvegg 200:2095643:6 | Level 02
Enfløyet:ID06 Tredør 10x21M:1964431:1 | Level 01
Enfløyet:ID08 11x21M EI60CSa:1964432:1 | Level 01
M_Door_ID_Cased-Opening:1200 x 2110mm 2:1964433:1 | Level 01
Enfløyet:ID05 Komposittdør 10x21M:1964434:1 | Level 01
Enfløyet:ID05 Komposittdør 10x21M:1964435:1 | Level 01
Enfløyet:ID09 ståldør 13x21M EI30 2:1964436:1 | Level 01
Åpningsvindu:V02 8x19M:1964464:1 | Level 02
Fastvindu:V01 13x19M:1964465:1 | Level 02
Fastvindu:V01 13x19M:1964466:1 | Level 02
Garage Door_3:P03 2500 x 2100:1964530:1 | Level 01
Enfløyet:ID07 Tredør 10x21M EI60:1964855:1 | Level 01
Enfløyet:ID06 Tredør 10x21M:1964948:1 | Level 01
Enfløyet:ID06 Tredør 10x21M:1964949:1 | Level 01
Enfløyet:ID11 Tredør 10x21M:1964950:1 | Level 01
Enfløyet:ID04 Tredør 9x21M:1964951:1 | Level 01
Enfløyet:ID04 Tredør 9x21M:1964952:1 | Level 01
Enfløyet:ID11 Tredør 10x21M:1964953:1 | Level 01
Enfløyet:ID04 Tredør 9x21M:1964973:1 | Level 01
M_Door_ID_Cased-Opening:910 x 2110mm:1965007:1 | Level 01
M_Door_ID_Cased-Opening:910 x 2110mm:1965008:1 | Level 01
Garage Door_9:4200 x 4500:1965248:1 | Level 01
ASSA_ABLOY_FoldingDoor_FD2350P_2+2_Manual:42x45:1967829:1 | Level 01
ASSA_ABLOY_FoldingDoor_FD2350P_2+2_Manual:42x45:1967928:1 | Level 01
Fastvindu:V03 Fastvindu 14x10M:1968759:1 | Level 02
Fastvindu:V03 Fastvindu 14x10M:1968941:1 | Level 02
Fastvindu:V03 Fastvindu 14x10M:1968995:1 | Level 02
Fastvindu:V03 Fastvindu 14x10M:1969089:1 | Level 02
Fastvindu:V03 Fastvindu 14x10M:1969251:1 | Level 02
Fastvindu:V03 Fastvindu 14x10M:1969471:1 | Level 02
Enfløyet:YD02 Ytterdør 11x21M mørk grå:1970705:1 | Level 01
Garage Door_9:P04 2700 x 3000:1971641:1 | Level 01
Enfløyet:ID02 11x21M:1992485:1 | Level 02
Enfløyet:ID03 Tredør 11x21M - EI30:1992797:1 | Level 02
Fastvindu:V01 13x19M:1994775:1 | Level 02
Fastvindu:V01 13x19M:2005449:1 | Level 02
Enfløyet:YD01 Glassdør sprosse 11x21M:2075855:1 | Level 01
Tofløyet:ID12 Stålsdør 16x21M EI30Sa:2076329:1 | Level 01
Enfløyet:ID13 Ståldør 10x21M EI30Sa:2077570:1 | Level 01
Enfløyet:ID11 Tredør 10x21M:2085154:1 | Level 01
Tofløyet:ID14 Tredør 16x21M EI30Sa:2085995:1 | Level 01
Enfløyet:ID03 Tredør 11x21M - EI30:2086316:1 | Level 02
Garage Door_9:4200 x 4500 P02B:2087061:1 | Level 01
Enfløyet:YD02 Ytterdør 11x21M mørk grå:2087068:1 | Level 01
Enfløyet:ID1 Glassdør 11x21M 38dB:2087617:1 | Level 02
Enfløyet:ID10 Stålsdør 10x21M:2092397:1 | Level 01
Enfløyet:ID04 Tredør 9x21M:2092488:1 | Level 01
Åpningsvindu:V04 8x19M:2126264:1 | Level 02

# IfcRailing: Railing:1100mm Stål Ø30 cc120 (3)
Material: <Unnamed>, Tre
Name (Railing:1100mm Stål Ø30 cc120:...) | In
1981258 | Level 02
2088689 | Level 01
2088693 | Level 01

# IfcRailing: Railing:900, Railing:900:1964999
In: Level 01
Material: <Unnamed>

# IfcRailing: Railing:900mm pipe, Railing:900mm pipe:1964995
In: Level 01
Material: <Unnamed>

# IfcRailing: Railing:Rekkverk 900mm rør - Top Rail, Railing:Rekkverk 900mm rør - Top Rail:1965037
In: Level 01
Material: <Unnamed>

# IfcRoof: Basic Roof:Warm Roof - TRP, Basic Roof:Warm Roof - TRP:1964443
In: Level 3
Material: NO_Asfaltpapp, NO_Isolasjon - Fast (2), <Unnamed>, Tak - Metall

# IfcSlab: Basic Roof:Standard 150 (2)
In: Level 02
Type - PredefinedType: ROOF
Material: Default Roof(1)
Name (Basic Roof:Standard 150:...)
2083605
2084034

# IfcSlab: Floor:Gulv på grunn 120mm, Floor:Gulv på grunn 120mm:1964344
In: Level 01
Type - PredefinedType: FLOOR

# IfcSlab: Floor:HD-320 mesanin +30mm, Floor:HD-320 mesanin +30mm:1981251
In: Level 02
Type - PredefinedType: FLOOR

# IfcSlab: Floor:HD-320+ isolasjon og avretting, Floor:HD-320+ isolasjon og avretting:1964411
In: Level 02
Type - PredefinedType: FLOOR

# IfcSlab: Floor:Rist, Floor:Rist:1965030
In: Level 01
Type - PredefinedType: FLOOR

# IfcSlab: Non-Monolithic Landing:Ikke monolittisk trappeavsats, Assembled Stair:Stair:2088389 Landing 1
In: Level 01
Type - PredefinedType: LANDING
Material: Stål

# IfcStair: Assembled Stair:Ståltrapp A, Assembled Stair:Stair:2088389
In: Level 01
Type - PredefinedType: HALF_TURN_STAIR

# IfcStair: Assembled Stair:Ståltrapp A, Assembled Stair:Stair:1964990
In: Level 01
Type - PredefinedType: STRAIGHT_RUN_STAIR

# IfcStairFlight: Non-Monolithic Run:Stål Trinn 30mm (3)
In: Level 01
Type - PredefinedType: STRAIGHT
Material: Stål
Name (Assembled Stair:Stair:...)
1964990 Run 1
2088389 Run 1
2088389 Run 2

# IfcWall: Basic Wall:IV01 - Gipsx2 Stender Gipsx2-147mm (3)
In: Level 01
Type - PredefinedType: STANDARD
Name (Basic Wall:IV01 - Gipsx2 Stender Gipsx2-147mm:...)
1964341
2084480
2085877

# IfcWall: Basic Wall:IV02 Gips Stender Gips-120mm (11)
Type - PredefinedType: STANDARD
Name (Basic Wall:IV02 Gips Stender Gips-120mm:...) | In
1964942 | Level 01
1964962 | Level 01
1964972 | Level 01
1964980 | Level 01
1964981 | Level 01
1965239 | Level 01
1993638 | Level 02
1993686 | Level 02
2091519 | Level 01
2091576 | Level 01
2091616 | Level 01

# IfcWall: Basic Wall:IV03 Gips Stender Forestia 120mm (2)
In: Level 01
Type - PredefinedType: STANDARD
Name (Basic Wall:IV03 Gips Stender Forestia 120mm:...)
1964374
1964375

# IfcWall: Basic Wall:IV04 - Gipsx2 Stender-kryssfiner- Gips-147mm, Basic Wall:IV04 - Gipsx2 Stender-kryssfiner- Gips-147mm:1992476
In: Level 02
Type - PredefinedType: STANDARD

# IfcWall: Basic Wall:IV05 - Forestia+Gips- Stender-kryssfiner- Gips (4)
Type - PredefinedType: STANDARD
Name (Basic Wall:IV05 - Forestia+Gips- Stender-kryssfiner- Gips:...) | In
1965022 | Level 01
1965108 | Level 01
1965109 | Level 01
1992478 | Level 02

# IfcWall: Basic Wall:IV07 Gips 95 stålstender +15mm kryssfiner+baderomsplater (2)
In: Level 01
Type - PredefinedType: STANDARD
Name (Basic Wall:IV07 Gips 95 stålstender +15mm kryssfiner+baderomsplater:...)
1964376
1964761

# IfcWall: Basic Wall:IV08 Forestia 95 stålstender +15mm kryssfiner+baderomsplater 2 (4)
In: Level 01
Type - PredefinedType: STANDARD
Name (Basic Wall:IV08 Forestia 95 stålstender +15mm kryssfiner+baderomsplater 2:...)
1964943
1964966
1965195
1965196

# IfcWall: Basic Wall:IV09 Badromsplate+15mm kryssf+ 95 stålstender +15mm kryssfiner+baderomsplater 2 (2)
In: Level 01
Type - PredefinedType: STANDARD
Name (Basic Wall:IV09 Badromsplate+15mm kryssf+ 95 stålstender +15mm kryssfiner+baderomsplater 2:...)
1964959
1964988

# IfcWall: Basic Wall:IV10 Forestia 95 Stender Forestia (3)
In: Level 01
Type - PredefinedType: STANDARD
Name (Basic Wall:IV10 Forestia 95 Stender Forestia:...)
1964974
1964975
1964989

# IfcWall: Basic Wall:IV11 95 Utforing 15mm kryssfiner baderomsplater 2 (2)
In: Level 01
Type - PredefinedType: STANDARD
Name (Basic Wall:IV11 95 Utforing 15mm kryssfiner baderomsplater 2:...)
1964985
1965105

# IfcWall: Basic Wall:IV12 Utforing Stender(48)-Forestia (3)
In: Level 01
Type - PredefinedType: STANDARD
Name (Basic Wall:IV12 Utforing Stender(48)-Forestia:...)
1964856
1965210
1970236

# IfcWall: Basic Wall:IV13 Utforing 198 stender+Forestia, Basic Wall:IV13 Utforing 198 stender+Forestia:1964977
In: Level 01
Type - PredefinedType: STANDARD

# IfcWall: Basic Wall:IV14 Gips 95 Stender kryssfiner Gips, Basic Wall:IV14 Gips 95 Stender kryssfiner Gips:1964760
In: Level 01
Type - PredefinedType: STANDARD

# IfcWall: Basic Wall:IV15 Gips kryssfiner 95 stålstender +15mm kryssfiner+baderomsplater 2 (3)
In: Level 01
Type - PredefinedType: STANDARD
Name (Basic Wall:IV15 Gips kryssfiner 95 stålstender +15mm kryssfiner+baderomsplater 2:...)
1964944
1964960
1965197

# IfcWall: Basic Wall:IV16 -Utforing Gips 198Stender 13+198, Basic Wall:IV16 -Utforing Gips 198Stender 13+198:1964983
In: Level 01
Type - PredefinedType: STANDARD

# IfcWall: Basic Wall:IV17 - Utforing lekt+fasadeplater (6)
Type - PredefinedType: STANDARD
Name (Basic Wall:IV17 - Utforing lekt+fasadeplater:...) | In
1964746 | Level 01
1964747 | Level 01
1964748 | Level 01
1965144 | Level 02
1965145 | Level 02
1965146 | Level 02

# IfcWall: Basic Wall:IV18 -Gips kryssfiner Stender kryssfiner-baderomsplater-13+15+200+15+11, Basic Wall:IV18 -Gips kryssfiner Stender kryssfiner-baderomsplater-13+15+200+15+11:1964765
In: Level 01
Type - PredefinedType: STANDARD

# IfcWall: Basic Wall:IV20 242- Utforing isolert Stender(95) gips, Basic Wall:IV20 242- Utforing isolert Stender(95) gips:1964762
In: Level 02
Type - PredefinedType: STANDARD

# IfcWall: Basic Wall:IV21 Betong 200 (6)
Type - PredefinedType: STANDARD
Name (Basic Wall:IV21 Betong 200:...) | In
1964372 | Level 01
1964373 | Level 01
1964384 | Level 02
1964717 | Level 01
1964956 | Level 01
1992466 | Level 02

# IfcWall: Basic Wall:IV23 Dusjvegg (3)
In: Level 01
Type - PredefinedType: STANDARD
Name (Basic Wall:IV23 Dusjvegg:...)
1965005
1965006
1965024

# IfcWall: Basic Wall:IV24 - Forestia+Gips- Stende4+2xgips, Basic Wall:IV24 - Forestia+Gips- Stende4+2xgips:1964921
In: Level 02
Type - PredefinedType: STANDARD

# IfcWall: Basic Wall:IV25 - 2xGips- Stende4+2xgips 2, Basic Wall:IV25 - 2xGips- Stende4+2xgips 2:1964922
In: Level 02
Type - PredefinedType: STANDARD

# IfcWall: Basic Wall:RIB YV-Betong_250mm+100iso (6)
In: Level 01
Type - PredefinedType: STANDARD
Name (Basic Wall:RIB YV-Betong_250mm+100iso:...)
1964885
1964887
1971344
2087058
2087059
2087067

# IfcWall: Basic Wall:YV02 Sandwichvegg 200 (19)
Type - PredefinedType: STANDARD
Name (Basic Wall:YV02 Sandwichvegg 200:...) | In
1964336 | Level 01
1964338 | Level 01
1964339 | Level 01
1964380 | Level 02
1964381 | Level 02
1964448 | Level 3
1964449 | Level 3
1964450 | Level 3
1964451 | Level 3
1971143 | Level 01
1986782 | Level 02
2080388 | Level 02
2087047 | Level 01
2087048 | Level 01
2087049 | Level 01
2087415 | Level 02
2094941 | Level 01
2095643 | Level 02
2095968 | Level 3

# IfcWall: Basic Wall:YV02 Sandwichvegg 200 rød (4)
Type - PredefinedType: STANDARD
Name (Basic Wall:YV02 Sandwichvegg 200 rød:...) | In
1964378 | Level 02
2094861 | Level 01
2095347 | Level 02
2096150 | Level 3

# IfcWindow: Fastvindu:V01 13x19M (4)
In: Level 02
Type - PredefinedType: WINDOW; Material: NO_Maling - mørk grå, NO_Glass - Klart, Hvit
OverallHeight: 1910 mm; OverallWidth: 1310 mm
Name (Fastvindu:V01 13x19M:...)
1964465
1964466
1994775
2005449

# IfcWindow: Fastvindu:V03 Fastvindu 14x10M (6)
In: Level 02
Type - PredefinedType: WINDOW; Material: NO_Maling - mørk grå, NO_Glass - Klart, Hvit
OverallHeight: 1010 mm; OverallWidth: 1410 mm
Name (Fastvindu:V03 Fastvindu 14x10M:...)
1968759
1968941
1968995
1969089
1969251
1969471

# IfcWindow: Åpningsvindu:V02 8x19M, Åpningsvindu:V02 8x19M:1964464
In: Level 02
Type - PredefinedType: WINDOW; Material: NO_Maling - mørk grå, NO_Glass - Klart
OverallHeight: 1910 mm; OverallWidth: 810 mm

# IfcWindow: Åpningsvindu:V04 8x19M, Åpningsvindu:V04 8x19M:2126264
In: Level 02
Type - PredefinedType: WINDOW; Material: NO_Maling - mørk grå, NO_Glass - Klart, Hvit
OverallHeight: 1910 mm; OverallWidth: 810 mm
